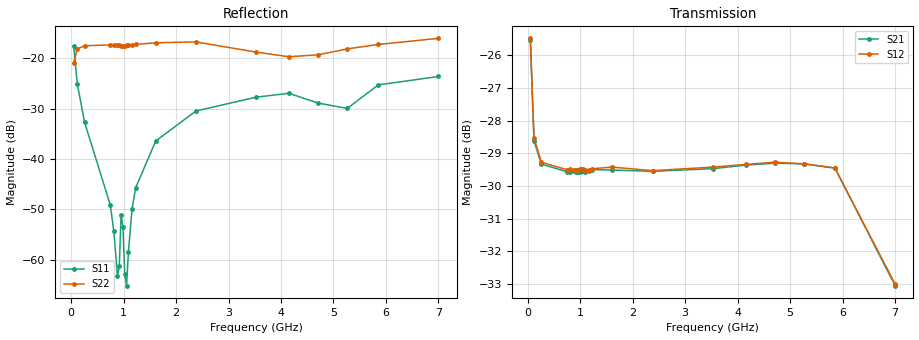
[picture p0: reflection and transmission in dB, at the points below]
! Integrated Device Technology
! Corporate Headquarters
! 6024 Silver Creek Valley Road
! San Jose, CA 95138  USA
! Phone:  1-408-284-8200
! Toll Free:  1-800-223-1366
! Webpage:  http://www.idt.com/
! Timing and RF Division
! 515 Groton Road, Suite 102
! Westford, MA 01886-6024
! Device:  F2258
! Description: Voltage Variable RF Attenuator
! Frequency:  50.0 -  6000.00 MHz
! Package:  3x3 mm Thin QFN Plastic Package: 16 pin
! Ports:  2 RF, 2 DC
!  Pin  1  = NC
!  Pin  2  = NC
!  Pin  3  = RF2  = Port 2
!  Pin  4  = GND
!  Pin  5  = Vdd
!  Pin  6  = NC
!  Pin  7  = VCTRL
!  Pin  8  = NC
!  Pin  9  = GND
!  Pin 10  = RF1  = Port 1
!  Pin 11  = NC
!  Pin 12  = NC
!  Pin 13  = NC
!  Pin 14  = NC
!  Pin 15  = NC
!  Pin 16  = NC
! Vcntrl:  1.650 Volts
! Vdd:  +3.300 Volts
! Current:  1.161 mA
! Data:  The device was measured on a the F2258 evaluation board which has
!  individual transmission lines to the RF pins.  Data was collected
!  using a calibrated network analyzer.  The evaluation board was
!  de-embedded using a TRL calibration technique.
!  The reference plane is the edge of the package pin.
! Misc:  SN 10
!  Action Tracker AT0285
! Date Measured:  2014-12-10
! Date:  2016-01-13  MJV
! Note:
!  Integrated Device Technology supplies this data as a sample of measured
!  data at the package pin for this product.  Your particular data for this
!  product may vary.
!  Data was taken at 25 degrees C.
!  Integrated Device Technology reserves the right to change this data at anytime.
!Freq_(GHz)  S11M_(dB)  S11P_(deg)  S21M_(dB)  S21P_(deg)  S12M_(dB)  S12P_(deg)  S22M_(dB)  S22P_(deg)
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# GHz S dB R 50
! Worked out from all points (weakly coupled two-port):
!   201 points, 50 MHz to 7 GHz, reference 50 ohm
!   highest |S21| = -25.52 dB at 50 MHz (marker M1); lowest = -33.0 dB at 7 GHz (marker M2)
!   lowest |S11| = -65.2 dB at 1.058 GHz (marker M3), VSWR 1.00, Z = 50.1 + j0.000812 ohm
!   |S11| at or under -10 dB: start of sweep to end of sweep
!   |S22| runs from -20.8 to -16.0 dB; largest |S21 - S12| = 0.0004
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0.05  -17.53 -109.8  -25.52 -49.4  -25.48 -49.3  -20.84 -38.6
0.1195  -25.12 -104.8  -28.61 -26.5  -28.52 -26.5  -18.08 -11.2
0.2585  -32.72 -107.5  -29.33 -14.7  -29.27 -14.7  -17.48 -6.9
0.745  -49.03 -120.7  -29.56 -10.8  -29.50 -10.8  -17.31 -10.0
0.8145  -54.27 -126.7  -29.56 -11.0  -29.49 -11.0  -17.30 -10.8
0.884  -63.22 171.6  -29.55 -11.2  -29.51 -11.2  -17.35 -12.0
0.91875  -61.33 119.3  -29.56 -11.4  -29.50 -11.4  -17.35 -12.5
0.9535  -51.01 -142.2  -29.57 -11.5  -29.50 -11.5  -17.54 -12.1
0.98825  -53.39 -154.2  -29.56 -11.6  -29.49 -11.6  -17.52 -12.9
1.023  -62.81 -156.9  -29.55 -11.8  -29.49 -11.8  -17.45 -13.4
1.05775  -65.15 0.8  -29.55 -11.9  -29.49 -12.0  -17.41 -13.6
1.0925  -58.48 28.0  -29.56 -12.1  -29.50 -12.1  -17.39 -14.0
1.162  -49.93 35.7  -29.54 -12.5  -29.50 -12.5  -17.30 -14.8
1.2315  -45.66 27.8  -29.50 -13.0  -29.47 -13.0  -17.20 -15.6
1.61375  -36.40 26.9  -29.51 -16.1  -29.42 -16.2  -16.89 -20.0
2.37825  -30.45 44.8  -29.55 -22.3  -29.53 -22.3  -16.71 -27.4
3.525  -27.69 90.0  -29.47 -32.5  -29.42 -32.5  -18.74 -45.0
4.1505  -26.93 104.3  -29.36 -38.6  -29.34 -38.6  -19.66 -61.7
4.7065  -28.86 94.7  -29.30 -44.1  -29.27 -44.2  -19.28 -71.3
5.2625  -29.93 51.9  -29.32 -50.5  -29.32 -50.4  -18.10 -74.0
5.85325  -25.26 28.3  -29.45 -58.9  -29.45 -58.9  -17.22 -74.1
7  -23.58 83.7  -33.05 -72.1  -33.00 -72.1  -16.01 -131.3
